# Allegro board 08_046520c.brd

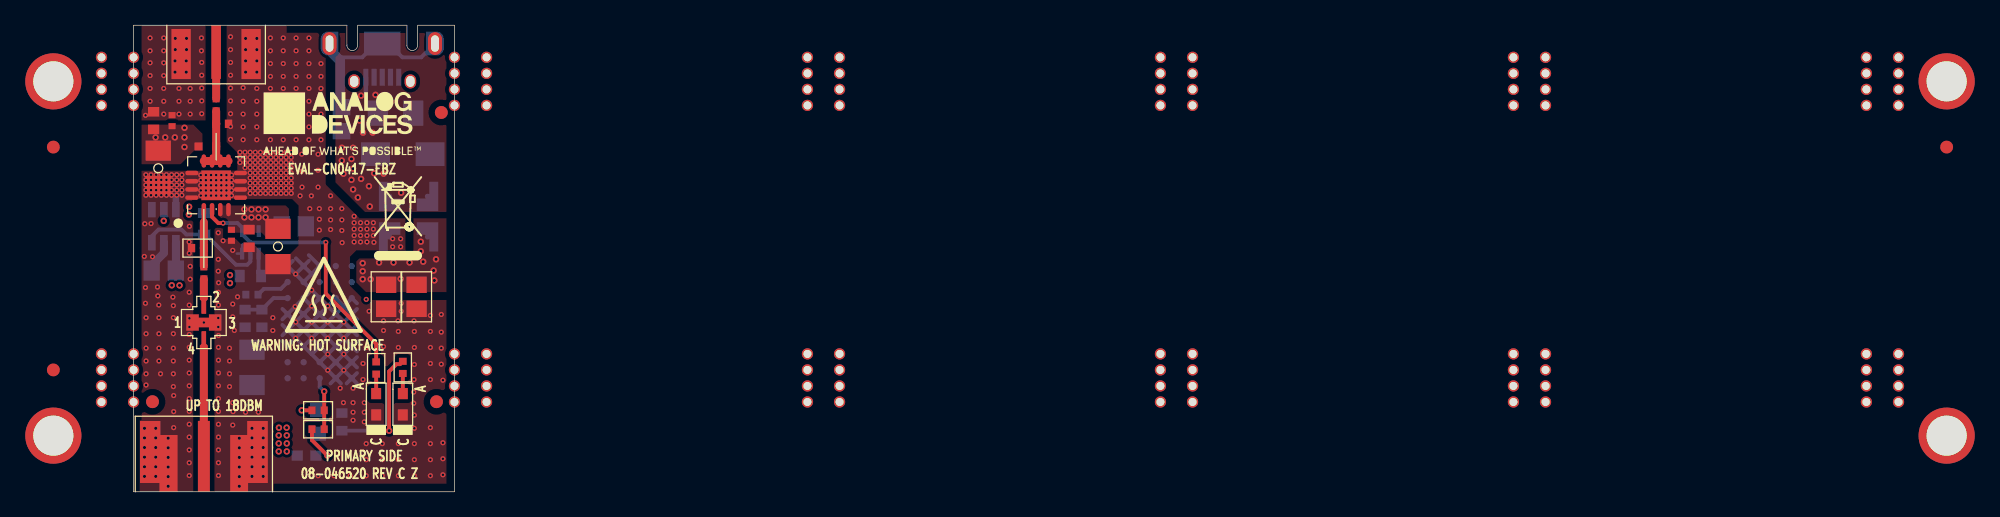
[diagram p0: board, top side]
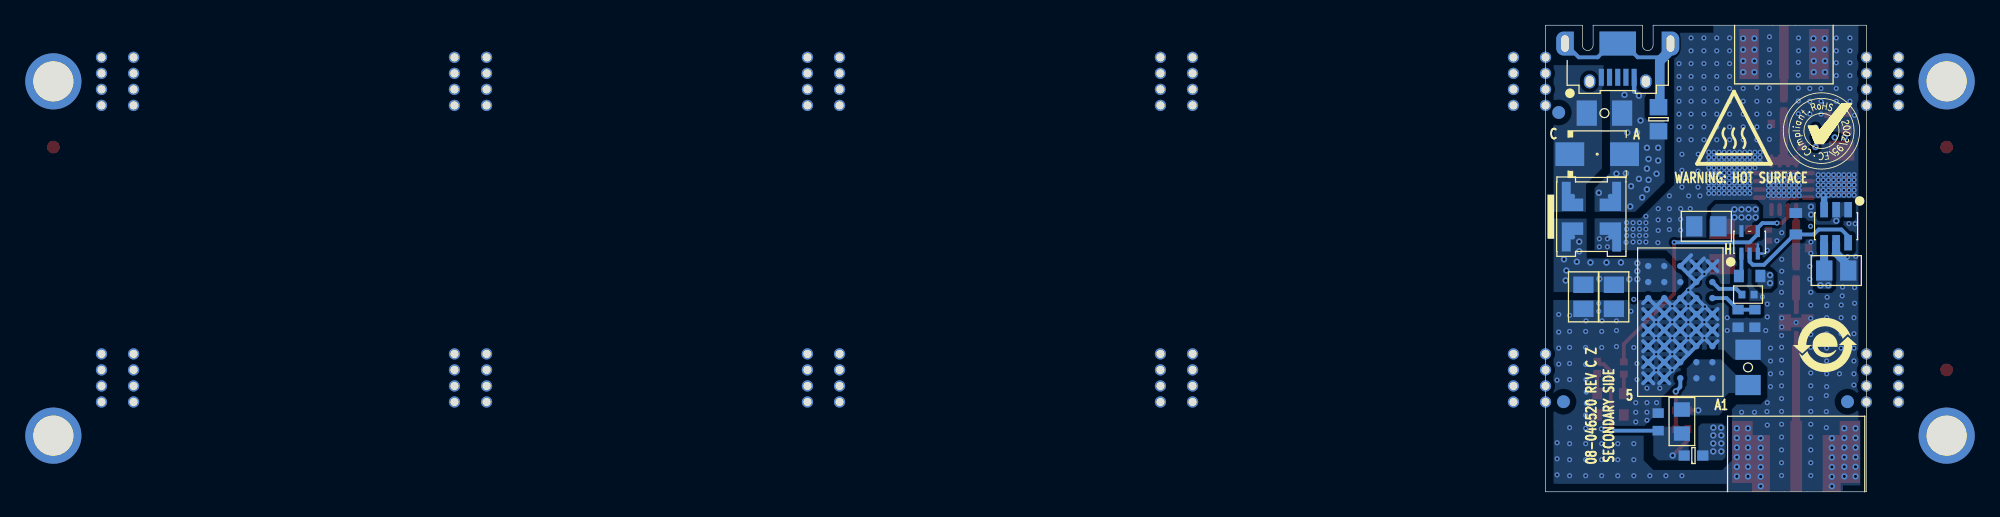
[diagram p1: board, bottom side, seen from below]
Outline 25.4 x 36.96 mm; copper layers: TOP, L2_GND, L3_GND, L4_PWR, L5_GND, BOTTOM. Coordinates in mm from the lower left corner of the outline.
Outline path: 0,36.96 16.88,36.96 16.88,35.38 arc(17.31,34.96) 17.74,35.38 17.74,36.96 21.63,36.96 21.63,35.38 arc(22.06,34.96) 22.49,35.38 22.49,36.96 25.4,36.96 25.4,0 0,0 0,36.96

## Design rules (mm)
constraint set DEFAULT: min track width 0.203
net group AMP: nets UNNAMED_7_ADL5606_I18_RFIN UNNAMED_7_ADL5606_I18_RFOUT1 UNNAMED_7_CAP_I75_N1 UNNAMED_7_CAP_I76_N2 UNNAMED_7_CNBNC5P_I149_CNTR UNNAMED_7_LINLTM8045_I104_FB

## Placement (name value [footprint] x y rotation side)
A1  ADL5606ACPZ  [QFN16_4X4_PAD2_36X2_36]  6.54 24.28 0 top
C1  20PF  [C0402#2]  5.56 17.34 90 top
C2  47UF  [C1206H71]  20.74 29.99 0 bottom
C3  4.7UF  [C0805H53]  22.4 15.44 90 bottom
C4  0.1UF  [C0805H53]  19.99 15.44 90 top
C5  0.1UF  [C0805H53]  22.4 15.44 90 top
C6  1UF  [C0603]  10.16 13.73 90 bottom
C7  0.1UF  [C0805H53]  19.99 15.44 90 bottom
C8  20PF  [C0402#2]  6.54 30.65 90 top
C9  1UF  [C0603]  8.83 13.73 90 bottom
C10  10UF  [C1206H71]  11.43 19.43 270 top
C11  0.01UF  [C0603]  9.14 20.07 270 top
C12  100pF  [C0402#2]  7.75 20.32 270 top
C13  10UF  [C1206H71]  1.96 25.63 270 top
C14  0.01UF  [C0603]  1.59 29.4 90 top
C15  100pF  [C0402#2]  3.05 29.4 90 top
C16  100uF  [C1206H71]  9.37 9.85 270 bottom
C17  1UF  [C0603]  16.48 5.53 270 bottom
C18  0.1UF  [C0805H53]  2.39 17.52 0 bottom
C19  0.1UF  [C0805H53]  12.67 21.03 180 bottom
CIN  2pF  [C0402]  5.07 19.3 0 top
COUT  3.3PF  [C0402]  7.03 29.15 180 top
D1  SMAJ5.0A-13-F  [DIOSMJ5_0]  21.31 26.74 180 bottom
DS1  LTST-C191KGKT  [LED0603_A]  21.31 6.93 90 top
DS2  SML-D12U1WT86  [LED0603_A]  19.2 6.93 90 top
E1  600OHM AT 100MEGHZ  [L0603]  13.69 2.87 180 bottom
FL1  2400-2500MEGHZ  [FL0805_A]  5.56 13.41 270 top
J1  132365-10  [CNSMARAL686W375H177]  5.56 0 270 top
J2  CON-SMA-EDGE-S  [CNSMARAL525W250H148]  6.53 36.96 90 top
L1  800OHMS AT 100MEGHZ  [L2020_A]  21.77 21.79 270 bottom
L2  18NH  [L7144A]  5.84 27.36 180 top
L3  1uH  [L0805]  14.61 5.56 270 bottom
NOREF  -  [unnamed]  109.22 31.88 0 top
NOREF#2  -  [unnamed]  -2.54 30.61 0 top
NOREF#3  -  [#2]  -6.35 4.44 0 top
NOREF#4  -  [unnamed]  0 8.38 0 top
NOREF#5  -  [unnamed]  83.82 33.15 0 top
NOREF#6  -  [unnamed]  25.4 30.61 0 top
NOREF#7  -  [unnamed]  109.22 10.92 0 top
NOREF#8  -  [unnamed]  23.98 7.13 0 top
NOREF#9  -  [unnamed]  137.16 10.92 0 top
NOREF#10  -  [#2]  25.4 0 0 top
NOREF#11  -  [#2]  27.94 0 0 top
NOREF#12  -  [unnamed]  27.94 33.15 0 top
NOREF#13  -  [unnamed]  27.94 9.65 0 top
NOREF#14  -  [unnamed]  0 30.61 0 top
NOREF#15  -  [unnamed]  81.28 9.65 0 top
NOREF#16  -  [#2]  -85.24 -81.42 0 top
NOREF#17  -  [#2]  18.41 36.96 180 top
NOREF#18  -  [unnamed]  24.36 30.05 0 top
NOREF#19  -  [unnamed]  139.7 30.61 0 top
NOREF#20  -  [unnamed]  -2.54 31.88 0 top
NOREF#21  -  [unnamed]  27.94 10.92 0 top
NOREF#22  -  [unnamed]  -2.54 34.42 0 top
NOREF#23  -  [unnamed]  111.76 9.65 0 top
NOREF#24  -  [unnamed]  83.82 31.88 0 top
NOREF#25  -  [unnamed]  139.7 10.92 0 top
NOREF#26  -  [unnamed]  83.82 34.42 0 top
NOREF#27  -  [#2]  83.82 0 0 top
NOREF#28  -  [unnamed]  137.16 33.15 0 top
NOREF#29  -  [#2]  200.49 202.45 0 top
NOREF#30  -  [unnamed]  -6.35 32.51 0 top
NOREF#31  -  [unnamed]  -2.54 7.11 0 top
NOREF#32  -  [unnamed]  53.34 31.88 0 top
NOREF#33  -  [unnamed]  0 33.15 0 top
NOREF#34  -  [#2]  200.49 216.62 0 top
NOREF#35  -  [unnamed]  -2.54 10.92 0 top
NOREF#36  -  [unnamed]  111.76 33.15 0 top
NOREF#37  -  [unnamed]  137.16 30.61 0 top
NOREF#38  -  [#2]  16.2 29.14 0 top
NOREF#39  -  [#2]  18.41 0 90 top
NOREF#40  -  [unnamed]  53.34 7.11 0 top
NOREF#41  -  [#2]  109.22 0 0 top
NOREF#42  -  [#2]  55.88 0 0 top
NOREF#43  -  [unnamed]  111.76 7.11 0 top
NOREF#44  -  [unnamed]  143.51 4.44 0 top
NOREF#45  -  [unnamed]  139.7 8.38 0 top
NOREF#46  -  [#2]  -2.54 0 0 top
NOREF#47  -  [unnamed]  25.4 33.15 0 top
NOREF#48  -  [#2]  -10.16 0 0 top
NOREF#49  -  [unnamed]  -6.35 4.44 0 top
NOREF#50  -  [unnamed]  55.88 10.92 0 top
NOREF#51  -  [unnamed]  111.76 34.42 0 top
NOREF#52  -  [unnamed]  53.34 9.65 0 top
NOREF#53  -  [unnamed]  81.28 8.38 0 top
NOREF#54  -  [unnamed]  109.22 8.38 0 top
NOREF#55  -  [unnamed]  139.7 31.88 0 top
NOREF#56  -  [#2]  20.73 18.39 0 top
NOREF#57  -  [unnamed]  1.5 7.13 0 top
NOREF#58  -  [unnamed]  25.4 9.65 0 top
NOREF#59  -  [unnamed]  109.22 9.65 0 top
NOREF#60  -  [unnamed]  53.34 33.15 0 top
NOREF#61  -  [#2]  -85.24 -81.42 0 top
NOREF#62  -  [unnamed]  55.88 30.61 0 top
NOREF#63  -  [unnamed]  137.16 9.65 0 top
NOREF#64  -  [unnamed]  25.4 8.38 0 top
NOREF#65  -  [unnamed]  81.28 34.42 0 top
NOREF#66  -  [unnamed]  143.51 32.51 0 top
NOREF#67  -  [unnamed]  111.76 31.88 0 top
NOREF#68  -  [#2]  -26.51 208.38 0 top
NOREF#69  -  [unnamed]  111.76 30.61 0 top
NOREF#70  -  [#2]  13.18 55.23 0 top
NOREF#71  -  [#2]  53.34 0 0 top
NOREF#72  -  [unnamed]  27.94 34.42 0 top
NOREF#73  -  [unnamed]  27.94 30.61 0 top
NOREF#74  -  [unnamed]  25.4 31.88 0 top
NOREF#75  -  [unnamed]  55.88 9.65 0 top
NOREF#76  -  [unnamed]  -2.54 8.38 0 top
NOREF#77  -  [unnamed]  53.34 10.92 0 top
NOREF#78  -  [#2]  198.13 184.67 90 top
NOREF#79  -  [#2]  0 0 0 top
NOREF#80  -  [unnamed]  53.34 34.42 0 top
NOREF#81  -  [unnamed]  81.28 33.15 0 top
NOREF#82  -  [unnamed]  55.88 33.15 0 top
NOREF#83  -  [unnamed]  109.22 30.61 0 top
NOREF#84  -  [unnamed]  53.34 30.61 0 top
NOREF#85  -  [unnamed]  109.22 34.42 0 top
NOREF#86  -  [#2]  51.59 145.53 0 top
NOREF#87  -  [#2]  206.54 214.31 90 top
NOREF#88  -  [unnamed]  81.28 30.61 0 top
NOREF#89  -  [unnamed]  0 31.88 0 top
NOREF#90  -  [unnamed]  139.7 7.11 0 top
NOREF#91  -  [unnamed]  139.7 34.42 0 top
NOREF#92  -  [unnamed]  27.94 7.11 0 top
NOREF#93  -  [unnamed]  111.76 8.38 0 top
NOREF#94  -  [unnamed]  25.4 10.92 0 top
NOREF#95  -  [unnamed]  0 9.65 0 top
NOREF#96  -  [unnamed]  139.7 33.15 0 top
NOREF#97  -  [unnamed]  -2.54 33.15 0 top
NOREF#98  -  [unnamed]  27.94 31.88 0 top
NOREF#99  -  [unnamed]  27.94 8.38 0 top
NOREF#100  -  [unnamed]  -6.35 27.3 0 top
NOREF#101  -  [#2]  -10.16 0 0 top
NOREF#102  -  [unnamed]  83.82 8.38 0 top
NOREF#103  -  [#2]  -10.16 36.96 0 top
NOREF#104  -  [#2]  194.67 114.19 0 top
NOREF#105  -  [unnamed]  25.4 34.42 0 top
NOREF#106  -  [unnamed]  55.88 31.88 0 top
NOREF#107  -  [#2]  139.7 0 0 top
NOREF#108  -  [#2]  32.54 141.72 0 top
NOREF#109  -  [unnamed]  83.82 7.11 0 top
NOREF#110  -  [unnamed]  0 34.42 0 top
NOREF#111  -  [unnamed]  137.16 8.38 0 top
NOREF#112  -  [unnamed]  109.22 33.15 0 top
NOREF#113  -  [unnamed]  83.82 10.92 0 top
NOREF#114  -  [#2]  189.47 214.34 0 top
NOREF#115  -  [unnamed]  111.76 10.92 0 top
NOREF#116  -  [unnamed]  83.82 30.61 0 top
NOREF#117  -  [#2]  81.28 0 0 top
NOREF#118  -  [#2]  1.22 27.55 0 top
NOREF#119  -  [unnamed]  81.28 7.11 0 top
NOREF#120  -  [#2]  147.32 0 0 top
NOREF#121  -  [unnamed]  -2.54 9.65 0 top
NOREF#122  -  [unnamed]  55.88 8.38 0 top
NOREF#123  -  [unnamed]  81.28 31.88 0 top
NOREF#124  -  [unnamed]  83.82 9.65 0 top
NOREF#125  -  [#2]  -69.38 316.18 0 top
NOREF#126  -  [#2]  -3.73 90.19 0 top
NOREF#127  -  [unnamed]  137.16 34.42 0 top
NOREF#128  -  [#2]  111.76 0 0 top
NOREF#129  -  [#2]  211.28 183.01 0 top
NOREF#130  -  [#2]  137.16 0 0 top
NOREF#131  -  [#2]  -85.24 -81.42 0 top
NOREF#132  -  [unnamed]  0 7.11 0 top
NOREF#133  -  [unnamed]  139.7 9.65 0 top
NOREF#134  -  [unnamed]  143.51 27.3 0 top
NOREF#135  -  [#2]  189.47 173.78 0 top
NOREF#136  -  [unnamed]  137.16 7.11 0 top
NOREF#137  -  [unnamed]  55.88 34.42 0 top
NOREF#138  -  [unnamed]  53.34 8.38 0 top
NOREF#139  -  [#2]  202.86 220.23 90 top
NOREF#140  -  [unnamed]  0 10.92 0 top
NOREF#141  -  [#2]  0 0 0 top
NOREF#142  -  [#2]  -6.35 4.44 0 top
NOREF#143  -  [unnamed]  137.16 31.88 0 top
NOREF#144  -  [#2]  0 36.96 270 top
NOREF#145  -  [unnamed]  55.88 7.11 0 top
NOREF#146  -  [unnamed]  81.28 10.92 0 top
NOREF#147  -  [unnamed]  -6.35 9.65 0 top
NOREF#148  -  [unnamed]  109.22 7.11 0 top
NOREF#149  -  [unnamed]  25.4 7.11 0 top
NOREF#150  -  [#2]  3.28 11.63 180 bottom
NOREF#151  -  [unnamed]  23.98 7.13 180 bottom
NOREF#152  -  [unnamed]  1.5 7.13 180 bottom
NOREF#153  -  [unnamed]  24.36 30.05 180 bottom
P1  47590-0001  [CNMOLEX47590-0001]  19.69 36.96 270 bottom
R1  1K  [R0805]  16.46 29.51 90 bottom
R2  60.4K  [R0402]  14.61 6.45 180 top
R3  182K  [R0402]  14.61 4.95 180 top
R4  301  [R0402]  21.31 9.85 90 top
R5  1K  [R0603]  5.59 21.23 90 bottom
R6  0  [R0603]  9.25 17.09 180 bottom
R7  365  [R0402]  19.2 9.8 90 top
RT  115K  [R0402]  9.37 15.62 180 bottom
U1  LTM8045MPY#PBF  [BGA40]  14.73 13.44 90 bottom
U2  ADT6402SRJZ  [TSOT23_6]  2.4 21.04 0 bottom
U3  74AHCT1G126SE-7  [SOT353]  9.25 19.76 180 bottom

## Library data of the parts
A1 = ADL5606: User Part Number: UPN; Tolerance: N/A; alternate symbols: (); part number: ADL5606_SM-ADL5606ACPZ,E026828,QFN16_4X4_PAD2_36X2_36; tolerance: N/A
C1 C8 = CAP: Tolerance: 5; User Part Number: UPN; alternate symbols: C0402L_ALT; part number: CAP_SM-20PF,50V,5,E033239,C0402; tolerance: 5
C2 = CAP: Tolerance: 20; User Part Number: UPN; alternate symbols: (); part number: CAP_SM-47UF,10V,20,E028092,C1206H71; tolerance: 20
C3 = CAP: Tolerance: 10; User Part Number: UPN; alternate symbols: (); part number: CAP_SM-4.7UF,25V,10,E025752,C0805H53; tolerance: 10
C4 C5 C7 C18 C19 = CAP: Tolerance: 10; User Part Number: UPN; alternate symbols: (); part number: CAP_SM-0.1UF,50V,10,E033336,C0805H53; tolerance: 10
C6 C9 C17 = CAP: Tolerance: 10; User Part Number: UPN; alternate symbols: C0603L_ALT; part number: CAP_SM-1UF,25V,10,E025743,C0603; tolerance: 10
C10 C13 = CAP: Tolerance: 10; User Part Number: UPN; alternate symbols: (); part number: CAP_SM-10UF,10V,10,E027443,C1206H71; tolerance: 10
C11 C14 = CAP: Tolerance: 10; User Part Number: UPN; alternate symbols: C0603L_ALT; part number: CAP_SM-0.01UF,100V,10,E032297,C0603; tolerance: 10
C12 C15 = CAP: Tolerance: 5; User Part Number: UPN; alternate symbols: C0402L_ALT; part number: CAP_SM-100PF,50V,5,E022402,C0402; tolerance: 5
C16 = CAP: Tolerance: 20; User Part Number: UPN; alternate symbols: (); part number: CAP_SM-100UF,6.3V,20,E016591,C1206H71; tolerance: 20
CIN = CAP: Tolerance: 0.25pF; User Part Number: UPN; alternate symbols: C0402L_ALT; part number: CAP_SM-2PF,50V,0.25PF,E012548,C0402; tolerance: 0.25pF
COUT = CAP: Tolerance: 0.1PF; User Part Number: UPN; alternate symbols: C0402L_ALT; part number: CAP_SM-3.3PF,50V,0.1PF,E027135,C0402; tolerance: 0.1PF
D1 = DIO: Tolerance: N/A; User Part Number: UPN; alternate symbols: (); part number: DIO_SM-SMAJ5.0A-13-F,5V,N/A,E001108,DIOSMJ5_0; tolerance: N/A
DS1 = DIOLED: User Part Number: UPN; Tolerance: N/A; alternate symbols: (); part number: DIOLED_SM-LTST-C191KGKT,2V,N/A,E033001,LED0603_A; tolerance: N/A
DS2 = DIOLED: User Part Number: UPN; Tolerance: N/A; alternate symbols: (); part number: DIOLED_SM-SML-D12U1WT86,2.2V,N/A,E037111,LED0603_A; tolerance: N/A
E1 = FERRITE: Tolerance: 25; User Part Number: UPN; alternate symbols: (); part number: FERRITE_SM-600OHM AT 100MEGHZ,25,E028908,L0603; tolerance: 25
FL1 = FLTRBP4P_V2: User Part Number: UPN; Tolerance: N/A; alternate symbols: (); part number: FLTRBP4P_V2_SM-2400-2500MEGHZ,E023131,FL0805_A; tolerance: N/A
J1 = CNBNC5P: alternate symbols: (CNSMARAL686W375H177_CNSMARAL535W256H152); part number: CNBNC5P_SM-132365-10,E033180,CNSMARAL686W375H177; tolerance: N/A
J2 = CNBNC5P: Tolerance: N/A; User Part Number: UPN; alternate symbols: (); part number: CNBNC5P_SM-CON-SMA-EDGE-S,E028678,CNSMARAL525W250H148; tolerance: N/A
L1 = CHOKE4P: User Part Number: UPN; Tolerance: N/A; alternate symbols: (); part number: CHOKE4P_SM-800OHMS AT 100MEGHZ,N/A,E027130,L2020_A; tolerance: N/A
L2 = IND: Tolerance: 5; User Part Number: UPN; alternate symbols: (); part number: IND_SM-18NH,5,E029275,L7144A; tolerance: 5
L3 = IND: Tolerance: 20; User Part Number: UPN; alternate symbols: (L0805L); part number: IND_SM-1UH,20,E010399,L0805; tolerance: 20
P1 = CN5P_3SHLD: User Part Number: UPN; Tolerance: N/A; alternate symbols: (); part number: CN5P_3SHLD_SM-47590-0001,E015753,CNMOLEX47590-0001; tolerance: N/A
R1 = RES: Tolerance: 1; User Part Number: UPN; alternate symbols: (R0805L); part number: RES_SM-1K,E023448,1/3W,1,R0805; tolerance: 1
R2 = RES: Tolerance: 1; User Part Number: UPN; alternate symbols: (R0402L); part number: RES_SM-60.4K,E022436,1/10W,1,R0402; tolerance: 1
R3 = RES: Tolerance: 1; User Part Number: UPN; alternate symbols: (R0402L); part number: RES_SM-182K,E025180,1/10W,1,R0402; tolerance: 1
R4 = RES: Tolerance: 1; User Part Number: UPN; alternate symbols: (R0402L); part number: RES_SM-301,E011195,1/16W,1,R0402; tolerance: 1
R5 = RES: User Part Number: UPN; Tolerance: 1; alternate symbols: (R0603L); part number: RES_SM-1K,E003678,1/10W,1,R0603; tolerance: 1
R6 = RES: User Part Number: UPN; Tolerance: 5; alternate symbols: (R0603L); part number: RES_SM-0,E006826,1/10W,5,R0603; tolerance: 5
R7 = RES: Tolerance: 1; User Part Number: UPN; alternate symbols: (R0402L); part number: RES_SM-365,E028356,1/10W,1,R0402; tolerance: 1
RT = RES: Tolerance: 1; User Part Number: UPN; alternate symbols: (R0402L); part number: RES_SM-115K,E025179,1/10W,1,R0402; tolerance: 1
U1 = LINLTM8045: Tolerance: N/A; User Part Number: UPN; alternate symbols: (); part number: LINLTM8045_SM-LTM8045MPY#PBF,E028897,BGA40; tolerance: N/A
U2 = ADT6402: User Part Number: UPN; Tolerance: N/A; alternate symbols: (); part number: ADT6402_SM-ADT6402SRJZ,E035980,TSOT23_6; tolerance: N/A
U3 = 741G126: User Part Number: UPN; Tolerance: N/A; alternate symbols: (); part number: 741G126_SM-74AHCT1G126SE-7,E0371122,SOT353; tolerance: N/A

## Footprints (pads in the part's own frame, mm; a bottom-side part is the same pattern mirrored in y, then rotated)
BGA40
  round 0.508 smd: A1(-4.445,-2.54) A2(-4.445,-1.27) A3(-4.445,0) A4(-4.445,1.27) A5(-4.445,2.54) B1(-3.175,-2.54) B2(-3.175,-1.27) B3(-3.175,0) B4(-3.175,1.27) B5(-3.175,2.54) C1(-1.905,-2.54) C2(-1.905,-1.27) C3(-1.905,0) C4(-1.905,1.27) C5(-1.905,2.54) D1(-0.635,-2.54) D2(-0.635,-1.27) D3(-0.635,0) D4(-0.635,1.27) D5(-0.635,2.54) E1(0.635,-2.54) E2(0.635,-1.27) E3(0.635,0) E4(0.635,1.27) E5(0.635,2.54) F1(1.905,-2.54) F2(1.905,-1.27) F3(1.905,0) F4(1.905,1.27) F5(1.905,2.54) G1(3.175,-2.54) G2(3.175,-1.27) G3(3.175,0) G4(3.175,1.27) G5(3.175,2.54) H1(4.445,-2.54) H2(4.445,-1.27) H3(4.445,0) H4(4.445,1.27) H5(4.445,2.54)
C0402
  rect 0.584x0.66 smd: 1(-0.49,0) 2(0.49,0)
C0402#2
  rect 0.483x0.559 smd: 1(-0.438,0) 2(0.438,0)
C0603
  rect 0.762x0.889 smd: 1(-0.699,0) 2(0.699,0)
C0805H53
  rect 1.295x1.6 smd: 1(-0.953,0) 2(0.953,0)
C1206H71
  rect 1.6x2.007 smd: 1(-1.397,0) 2(1.397,0)
CNMOLEX47590-0001
  oval 1.118x0.914 hole 0.864x0.66: (4.45,-2.225) (4.45,2.225)
  rect 1.346x0.406 smd: 1(4.123,-1.3) 2(4.123,-0.65) 3(4.123,0) 4(4.123,0.65) 5(4.123,1.3)
  oval 1.803x1.118 hole 1.295x0.61: SH1(1.45,4.175) SH3(1.45,-4.175)
  rect 1.905x2.896 smd: SH2(1.45,0)
CNSMARAL525W250H148
  rect 4.242x0.762 smd: 1(-2.121,0)
  rect 3.962x1.499 smd: 2(-2.281,2.77) 3(-2.281,2.77) 4(-2.281,-2.77) 5(-2.281,-2.77)
CNSMARAL686W375H177
  rect 5.613x0.94 smd: 1(-2.807,0)
  custom 0.737x0.737 smd: 2(-2.801,3.576) 3(-2.801,-3.576) 4(-2.801,3.576) 5(-2.801,-3.576)
DIOSMJ5_0
  rect 2.286x1.88 smd: A(2.164,0) C(-2.164,0)
FL0805_A
  rect 1.295x0.986 smd: 1(0,-0.895) 3(0,0.895)
  rect 0.991x0.356 smd: 2(-1.195,0) 4(1.195,0)
L0603
  rect 0.889x0.813 smd: 1(-0.737,0) 2(0.737,0)
L0805
  rect 1.143x1.27 smd: 1(-0.953,0) 2(0.953,0)
L2020_A
  custom 0.425x0.425 smd: 1(-1.606,-1.501) 2(1.606,-1.501) 3(1.606,1.501) 4(-1.606,1.501)
L7144A
  rect 0.635x0.635 smd: 1(-0.699,0) 2(0.699,0)
LED0603_A
  rect 0.889x0.787 smd: A(0.845,0) C(-0.845,0)
QFN16_4X4_PAD2_36X2_36
  oval 0.356x1.041 smd: 1(-0.975,-1.925) 2(-0.325,-1.925) 3(0.325,-1.925) 4(0.975,-1.925) 9(0.975,1.925) 10(0.325,1.925) 11(-0.325,1.925) 12(-0.975,1.925)
  oval 1.041x0.356 smd: 5(1.925,-0.975) 6(1.925,-0.325) 7(1.925,0.325) 8(1.925,0.975) 13(-1.925,0.975) 14(-1.925,0.325) 15(-1.925,-0.325) 16(-1.925,-0.975)
  rect 2.352x2.352 smd: PAD(0,0)
R0402
  rect 0.559x0.61 smd: 1(-0.483,0) 2(0.483,0)
R0603
  rect 0.787x0.991 smd: 1(-0.85,0) 2(0.85,0)
R0805
  rect 1.295x1.397 smd: 1(-0.953,0) 2(0.953,0)
SOT353
  rect 0.33x0.94 smd: 1(-0.65,-0.89) 2(0,-0.89) 3(0.65,-0.89) 4(0.65,0.89) 5(-0.65,0.89)
TSOT23_6
  rect 0.61x1.219 smd: 1(-0.95,-1.31) 2(0,-1.31) 3(0.95,-1.31) 4(0.95,1.31) 5(0,1.31) 6(-0.95,1.31)
unnamed
  round 0.889 hole 0.635 unplated: (0,0)

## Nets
5V_VCC: A1.3(VCC) A1.4 C10.1 C11.1 C12.1 C13.1 C14.1 C15.1 C18.2(N2) C19.2(N2) E1.2(N2) L2.2(N2) R5.2(N2) R6.2(N2) U2.1 U2.2 U2.4(VCC) U3.5
GND: A1.5 A1.6 A1.7 A1.8 A1.13 A1.14 A1.15 A1.16 A1.PAD C3.1 C4.1 C5.1 C6.1 C7.1 C9.1 C10.2(N2) C11.2(N2) C12.2(N2) C13.2(N2) C14.2(N2) C15.2(N2) C16.1 C17.1 C18.1 C19.1 CIN.1 COUT.1 DS1.C DS2.C FL1.1 FL1.3 J1.2 J1.3 J1.4 J1.5(SH4) J2.2 J2.3 J2.4 J2.5(SH4) L1.3 RT.2(N2) U1.A4 U1.A5 U1.B3 U1.B4 U1.B5(VOUT-_4) U1.C1 U1.C2 U1.C3 U1.C4 U1.C5 U1.D1 U1.D2 U1.D3 U1.D4 U1.D5 U1.E1 U1.E2 U1.E3 U1.E4 U1.E5 U1.F2 U1.F3 U1.F4 U1.F5 U1.G2 U1.H1 U1.H2 U1.H3 U2.3 U2.5 U3.3
PGND: C2.1 D1.A(P) L1.4(N4) P1.5 R1.1
DISABLE: A1.2 R7.2(N2) U3.4(Y)
UNNAMED_7_741G126_I166_A: R5.1 U2.6 U3.2
UNNAMED_7_741G126_I166_OE: R6.1 U3.1
UNNAMED_7_ADL5606_I18_RFIN: A1.1 C1.2(N2) CIN.2(N2)
UNNAMED_7_ADL5606_I18_RFOUT1: A1.9 A1.10 A1.11 A1.12 C8.1 COUT.2(N2) L2.1
UNNAMED_7_CAP_I75_N1: C1.1 FL1.2(OUT)
UNNAMED_7_CAP_I76_N2: C8.2(N2) J2.1
UNNAMED_7_CAP_I108_N2: C16.2(N2) L3.1 R2.2(N2) U1.A1 U1.A2 U1.B1 U1.B2
UNNAMED_7_CAP_I113_N2: C3.2(N2) C4.2(N2) C5.2(N2) C7.2(N2) L1.2 U1.G3 U1.G4 U1.G5 U1.H4 U1.H5
UNNAMED_7_CAP_I120_N2: C2.2(N2) D1.C L1.1 P1.1
UNNAMED_7_CAP_I132_N2: C6.2(N2) C9.2(N2) U1.F1
UNNAMED_7_CN5P3SHLD_I127_N6: P1.SH1 P1.SH2 P1.SH3(N8) R1.2(N2)
UNNAMED_7_CNBNC5P_I149_CNTR: FL1.4 J1.1
UNNAMED_7_DIOLED_I150_P: DS1.A(P) R4.1
UNNAMED_7_DIOLED_I172_P: DS2.A(P) R7.1
UNNAMED_7_FERRITE_I107_N1: C17.2(N2) E1.1 L3.2(N2) R3.2(N2) R4.2(N2)
UNNAMED_7_LINLTM8045_I104_FB: R2.1 R3.1 U1.A3
UNNAMED_7_LINLTM8045_I104_RT: RT.1 U1.G1

Pads without a net: P1 2 3 4

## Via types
v1: diameter 0.406, hole 0.203, TOP to BOTTOM, 466 vias
v2: diameter 0.508, hole 0.254, TOP to BOTTOM, 119 vias

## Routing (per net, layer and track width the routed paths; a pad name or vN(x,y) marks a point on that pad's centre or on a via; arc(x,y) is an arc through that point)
5V_VCC: length 2.2
  BOTTOM w0.635: C18.2 3.35,17.53 U2.4
  vias: v2(1.74,28.07) v2(2.39,21.46) v2(2.51,28.07) v2(3.02,16.36) v2(3.27,28.07) v2(3.64,16.35) v2(4.03,28.83) v2(4.03,28.07) v2(4.03,27.31) v2(4.39,22.58) v2(4.38,21.96) v2(7.63,17.16) v2(7.63,16.53) v2(8.77,22.37) v2(8.77,21.74) v2(9.33,22.37) v2(9.33,21.74) v2(9.89,22.37) v2(9.89,21.74) v2(10.45,22.37) v2(10.45,21.74) v2(11.51,5.08) v2(11.49,4.46) v2(11.49,3.83) v2(11.49,3.19) v2(12.12,5.08) v2(12.13,4.46) v2(12.13,3.83) v2(12.13,3.19)
GND: length 86.8
  BOTTOM w0.203: 8.6,19.59 U3.3 8.18,18.87
  BOTTOM w0.305: U1.C4 v1(16.64,12.17) ; U1.C4 v1(15.37,10.9) ; U1.C4 v1(15.37,12.17) ; U1.C4 v1(16.64,10.9) ; v1(16.64,12.17) U1.D5 ; v1(16.64,12.17) U1.C5 ; v1(16.64,12.17) U1.D4 ; v1(14.1,15.98) U1.F2 ; v1(14.1,15.98) U1.F3 ; v1(14.1,15.98) U1.G2 ; U1.F2 v1(12.79,14.67) ; U1.F2 v1(14.1,14.71) ; 16.64,14.71 U1.E4 ; 16.64,14.71 U1.E5 ; 16.64,14.71 U1.F5 17.68,14.93 ; 16.64,14.71 U1.F4 v1(15.37,14.71) ; U1.E4 v1(15.37,14.71) ; U1.E4 v1(15.37,13.44) ; U1.E4 v1(16.64,13.44) ; 16.86,8.58 U1.A5 ; U1.A5 v1(16.64,9.63) ; U1.A5 17.68,9.4 ; U1.A5 17.68,8.58 ; v1(12.83,12.17) U1.D2 ; v1(12.83,12.17) U1.C2 ; v1(12.83,12.17) U1.C1 11.78,11.94 ; v1(12.83,12.17) U1.D1 ; U1.D2 v1(14.1,13.44) ; U1.D2 v1(12.83,13.44) ; U1.D2 v1(14.1,12.17) ; U1.F3 v1(14.1,14.71) ; U1.F3 v1(15.37,14.71) ; 14.1,10.9 U1.C3 ; 14.1,10.9 U1.C2 ; 14.1,10.9 U1.B3 ; U1.C3 v1(15.37,10.9) ; U1.C3 v1(15.37,12.17) ; U1.C3 v1(14.1,12.17) ; v1(12.79,14.67) U1.E1 ; v1(12.79,14.67) 13.39,14.07 U1.E2 ; U1.E1 v1(12.83,13.44) ; U1.E1 11.78,13.66 ; U1.E1 11.78,14.48 ; U1.B3 v1(15.37,9.63) ; U1.B3 v1(15.37,10.9) ; v1(15.37,9.63) U1.B4 ; v1(15.37,9.63) U1.A4 ; 13.87,18.74 U1.H3 14.1,17.25 ; U1.C5 17.68,11.12 ; U1.C5 v1(16.64,10.9) ; U1.C5 17.68,11.94 ; v1(15.37,14.71) U1.E3 ; v1(14.1,13.44) U1.D3 ; v1(14.1,13.44) U1.E2 ; v1(14.1,13.44) U1.E3 ; U1.D3 v1(15.37,12.17) ; U1.D3 v1(15.37,13.44) ; U1.D3 v1(14.1,12.17) ; U1.E2 v1(14.1,14.71) ; U1.E2 v1(12.83,13.44) ; v1(14.1,14.71) U1.E3 ; v1(15.37,10.9) U1.B4 ; U1.B4 v1(16.64,10.9) ; U1.B4 v1(16.64,9.63) ; U1.C2 v1(14.1,12.17) ; v1(12.83,13.44) U1.D1 ; U1.H2 v1(12.83,17.25) ; U1.H2 12.85,18.49 ; U1.H2 13.87,18.29 ; U1.H2 14.1,17.25 ; v1(12.83,17.25) U1.G2 ; v1(12.83,17.25) U1.H1 ; U1.G2 14.1,17.25 ; U1.D5 17.68,13.21 ; U1.D5 17.68,12.39 ; U1.D5 v1(16.64,13.44) ; v1(16.64,10.9) U1.B5 ; U1.D1 11.78,12.39 ; U1.D1 11.78,13.21 ; 15.59,8.58 U1.A4 ; U1.A4 16.41,8.58 ; U1.A4 v1(16.64,9.63) ; v1(16.64,9.63) U1.B5 ; U1.D4 v1(15.37,12.17) ; U1.D4 v1(15.37,13.44) ; U1.D4 v1(16.64,13.44) ; U1.E5 v1(16.64,13.44) ; U1.E5 17.68,13.66 ; U1.E5 17.68,14.48 ; U1.B5 17.68,10.67 ; U1.B5 17.68,9.85 ; U1.H1 11.78,17.47 ; U1.H1 12.6,18.29 ; U1.H1 11.78,18.29 ; U1.E3 v1(15.37,13.44)
  BOTTOM w0.508: v1(3.41,23.49) 3.35,23.43 U2.3
  BOTTOM w0.635: U2.5 2.4,18.91 1.43,17.94 C18.1
  vias: v1(0.89,21.23) v1(0.85,18.64) v1(0.95,29.82) v1(0.97,25.11) v1(0.97,24.71) v1(0.97,24.3) v1(0.97,23.9) v1(0.97,23.49) v1(0.94,16.18) v1(0.94,14.93) v1(0.99,13.79) v1(0.99,12.52) v1(0.99,11.38) v1(0.99,10.36) v1(0.99,9.34) v1(0.99,8.46) v1(1.31,35.95) v1(1.31,34.94) v1(1.31,33.98) v1(1.31,32.97) v1(1.31,31.95) v1(1.31,30.93) v1(1.38,25.11) v1(1.38,24.71) v1(1.38,24.3) v1(1.38,23.9) v1(1.38,23.49) v1(1.38,21.24) v1(1.5,18.62) v1(1.79,25.11) v1(1.79,24.71) v1(1.79,24.3) v1(1.79,23.9) v1(1.79,23.49) v1(1.89,16.22) v1(1.92,15.52) v1(1.99,14.79) v1(2.01,13.79) v1(2.01,12.52) v1(2.01,11.38) v1(2.01,10.36) v1(2.19,25.11) v1(2.19,24.71) v1(2.19,24.3) v1(2.19,23.9) v1(2.19,23.49) v1(2.13,9.34) v1(2.39,35.95) v1(2.39,34.94) v1(2.39,33.98) v1(2.39,32.97) v1(2.39,31.95) v1(2.39,30.93) v1(2.39,29.92) v1(2.6,25.11) v1(2.6,24.71) v1(2.6,24.3) v1(2.6,23.9) v1(2.6,23.49) v1(3.01,25.11) v1(3.01,24.71) v1(3.01,24.3) v1(3.01,23.9) v1(3.01,23.49) v1(3.11,15.42) v1(3.15,14.74) v1(3.15,13.79) v1(3.15,12.52) v1(3.15,11.38) v1(3.15,10.36) v1(3.15,9.34) v1(3.15,8.33) v1(3.17,7.62) v1(3.17,6.35) v1(3.17,5.08) v1(3.41,25.11) v1(3.41,24.71) v1(3.41,24.3) v1(3.41,23.9) v1(3.59,31.95) v1(3.59,30.93) v1(3.59,29.92) v1(3.82,25.11) v1(3.82,24.71) v1(3.82,24.3) v1(3.82,23.9) v1(3.82,23.49) v1(4.39,19.78) v1(4.41,18.89) v1(4.41,15.8) v1(4.41,14.79) v1(4.41,12.46) v1(4.41,11.44) v1(4.41,10.43) v1(4.41,9.41) v1(4.41,8.39) v1(4.41,7.38) v1(4.41,6.36) v1(4.41,5.35) v1(4.41,4.33) v1(4.41,3.31) v1(4.41,2.3) v1(4.41,1.28) v1(4.48,31.95) v1(4.48,30.93) v1(4.48,29.92) v1(4.42,21.03) v1(4.48,17.85) v1(4.48,16.84) v1(4.42,13.74) v1(4.42,13.05) v1(5.37,35.95) v1(5.37,34.94) v1(5.39,34.01) v1(5.39,33) v1(5.39,31.98) v1(5.39,30.96) v1(5.39,29.95) v1(5.32,25.09) v1(5.32,24.68) v1(5.32,24.28) v1(5.32,23.87) v1(5.32,23.46) v1(5.56,13.41) v1(5.72,25.09) v1(5.72,24.68) v1(5.72,24.28) v1(5.72,23.87) v1(5.72,23.46) v1(6.13,25.09) v1(6.13,24.68) v1(6.13,24.28) v1(6.13,23.87) v1(6.13,23.46) v1(6.54,25.09) v1(6.54,24.68) v1(6.54,24.28) v1(6.54,23.87) v1(6.54,23.46) v1(6.71,20.52) v1(6.71,18.41) v1(6.71,17.47) v1(6.71,13.76) v1(6.71,13.05) v1(6.73,16.56) v1(6.72,15.8) v1(6.72,14.79) v1(6.72,12.37) v1(6.72,11.44) v1(6.72,10.43) v1(6.72,9.41) v1(6.72,8.39) v1(6.72,7.38) v1(6.72,6.36) v1(6.72,5.35) v1(6.72,4.33) v1(6.72,3.31) v1(6.72,2.3) v1(6.72,1.28) v1(6.94,25.09) v1(6.94,24.68) v1(6.94,24.28) v1(6.94,23.87) v1(6.94,23.46) v1(7.09,19.89) v1(7.35,25.09) v1(7.35,24.68) v1(7.35,24.28) v1(7.35,23.87) v1(7.35,23.46) v1(7.59,11.38) v1(7.59,10.36) v1(7.59,9.34) v1(7.59,8.33) v1(7.68,36.04) v1(7.68,35.03) v1(7.68,34.01) v1(7.68,33) v1(7.68,31.98) v1(7.68,30.96) v1(7.68,29.95) v1(7.68,28.93) v1(7.68,27.92) v1(7.76,25.09) v1(7.76,24.68) v1(7.76,24.28) v1(7.76,23.87) v1(7.76,23.46) v1(7.85,19.12) v1(7.85,14.87) v1(7.85,13.85) v1(7.85,7.06) v1(7.87,6.35) v1(7.85,5.28) v1(7.98,12.77) v1(8.23,15.44) v1(8.42,26.89) v1(8.42,26.49) v1(8.42,26.08) v1(8.67,32.01) v1(8.67,30.93) v1(8.67,29.92) v1(8.67,28.9) v1(8.67,27.89) v1(8.82,26.89) v1(8.82,26.49) v1(8.82,26.08) v1(8.82,25.67) v1(8.86,6.3) v1(9.23,26.89) v1(9.23,26.49) v1(9.23,26.08) v1(9.23,25.67) v1(9.23,25.27) v1(9.23,24.86) v1(9.23,24.45) v1(9.23,24.05) v1(9.23,23.64) v1(9.64,26.89) v1(9.64,26.49) v1(9.64,26.08) v1(9.64,25.67) v1(9.64,25.27) v1(9.64,24.86) v1(9.64,24.45) v1(9.64,24.05) v1(9.64,23.64) v1(9.75,31.95) v1(9.75,30.93) v1(9.75,29.92) v1(9.75,28.9) v1(9.75,27.89) v1(9.88,6.3) v1(10.04,26.89) v1(10.04,26.49) v1(10.04,26.08) v1(10.04,25.67) v1(10.04,25.27) v1(10.04,24.86) v1(10.04,24.45) v1(10.04,24.05) v1(10.04,23.64) v1(10.45,26.89) v1(10.45,26.49) v1(10.45,26.08) v1(10.45,25.67) v1(10.45,25.27) v1(10.45,24.86) v1(10.45,24.45) v1(10.45,24.05) v1(10.45,23.64) v1(10.83,35.95) v1(10.83,34.94) v1(10.83,33.92) v1(10.83,32.9) v1(10.83,31.95) v1(10.83,30.93) v1(10.83,29.92) v1(10.83,28.9) v1(10.83,27.89) v1(10.86,26.89) v1(10.86,26.49) v1(10.86,26.08) v1(10.86,25.67) v1(10.86,25.27) v1(10.86,24.86) v1(10.86,24.45) v1(10.86,24.05) v1(10.86,23.64) v1(11.02,13.79) v1(11.02,12.77) v1(11.26,26.89) v1(11.26,26.49) v1(11.26,26.08) v1(11.26,25.67) v1(11.26,25.27) v1(11.26,24.86) v1(11.26,24.45) v1(11.26,24.05) v1(11.26,23.64) v1(11.67,26.89) v1(11.67,26.49) v1(11.67,26.08) v1(11.67,25.67) v1(11.67,25.27) v1(11.67,24.86) v1(11.67,24.45) v1(11.67,24.05) v1(11.67,23.64) v1(11.85,35.95) v1(11.85,34.94) v1(11.85,33.92) v1(11.85,32.9) v1(11.85,31.95) v1(11.85,30.93) v1(11.85,29.92) v1(11.85,28.9) v1(11.85,27.89) v1(12.07,26.89) v1(12.07,26.49) v1(12.07,26.08) v1(12.07,25.67) v1(12.07,25.27) v1(12.07,24.86) v1(12.07,24.45) v1(12.07,24.05) v1(12.07,23.64) v1(12.48,26.9) v1(12.48,26.49) v1(12.48,26.08) v1(12.48,25.67) v1(12.48,25.27) v1(12.48,24.86) v1(12.48,24.45) v1(12.48,24.05) v1(12.48,23.64) v1(12.86,35.95) v1(12.86,34.94) v1(12.86,33.92) v1(12.86,32.9) v1(12.86,31.95) v1(12.86,30.93) v1(12.86,29.92) v1(12.86,28.9) v1(12.86,27.89) v1(13.18,23.44) v1(13.31,26.74) v1(13.34,25.4) v1(13.34,24.13) v1(13.88,35.95) v1(13.88,34.94) v1(13.88,33.92) v1(13.88,32.9) v1(13.88,31.95) v1(13.88,30.93) v1(13.88,29.92) v1(13.88,28.9) v1(13.88,27.89) v1(13.94,22.43) v1(14.07,23.44) v1(14.61,26.73) v1(14.61,25.46) v1(14.61,24.13) v1(14.61,1.27) v1(14.71,22.43) v1(14.71,21.59) v1(14.71,20.72) v1(14.83,33.92) v1(14.83,32.9) v1(14.83,31.95) v1(14.83,30.93) v1(14.83,29.92) v1(14.83,28.9) v1(14.83,27.89) v1(15.6,23.44) v1(15.6,22.43) v1(15.6,21.54) v1(15.6,20.77) v1(15.88,1.27) v1(16.36,8.2) v1(16.48,22.43) v1(16.48,21.54) v1(16.48,20.7) v1(16.51,19.73) v1(16.61,7.06) v1(17.14,1.27) v1(17.37,8.2) v1(17.37,7.06) v1(17.37,6.3) v1(17.37,5.66) v1(17.46,21.82) v1(17.46,21.31) v1(17.46,20.8) v1(17.46,20.3) v1(17.46,19.79) v1(17.96,21.31) v1(17.96,20.8) v1(17.96,20.3) v1(17.96,19.79) v1(18.16,10.16) v1(18.16,8.89) v1(18.26,7.06) v1(18.26,6.3) v1(18.26,5.53) v1(18.47,21.31) v1(18.47,20.8) v1(18.47,20.3) v1(18.47,19.79) v1(18.41,15.24) v1(18.41,11.43) v1(18.41,3.81) v1(18.41,2.54) v1(18.41,1.27) v1(18.64,14.3) v1(18.98,21.31) v1(18.98,20.8) v1(18.98,20.3) v1(19.02,19.76) v1(19.69,3.81) v1(19.69,2.54) v1(19.69,1.27) v1(19.79,13.54) v1(19.79,12.77) v1(19.79,11.5) v1(20.5,20.04) v1(20.5,19.41) v1(20.93,13.54) v1(20.95,12.7) v1(20.95,11.43) v1(20.98,4.98) v1(20.95,3.81) v1(20.95,2.54) v1(20.95,1.27) v1(21.14,20.04) v1(21.14,19.41) v1(21.18,14.93) v1(21.18,14.3) v1(22.2,13.54) v1(22.2,8.89) v1(22.17,7.9) v1(22.17,7.01) v1(22.23,12.7) v1(22.23,11.43) v1(22.22,10.08) v1(22.22,6.07) v1(22.22,5.03) v1(22.23,3.81) v1(22.23,2.54) v1(22.23,1.27) v1(23.49,13.97) v1(23.49,12.7) v1(23.49,11.43) v1(23.49,10.16) v1(23.49,8.89) v1(23.49,5.08) v1(23.49,3.81) v1(23.49,2.54) v1(23.49,1.27) v1(24.36,14.04) v1(24.36,12.65) v1(24.36,11.38) v1(24.36,10.11) v1(24.49,8.84) v1(24.49,3.88) v1(24.49,2.61) v1(24.49,1.34) v2(0.86,5.03) v2(0.86,4.26) v2(0.86,3.5) v2(0.86,2.74) v2(0.86,1.98) v2(0.86,1.22) v2(1.75,5.03) v2(1.75,4.26) v2(1.75,3.5) v2(1.75,2.74) v2(1.75,1.98) v2(1.75,1.22) v2(2.74,4.24) v2(2.74,3.48) v2(2.74,2.72) v2(2.74,1.96) v2(2.74,1.2) v2(2.74,0.43) v2(3.3,35.92) v2(3.3,35.03) v2(3.28,34.13) v2(3.28,33.24) v2(4.19,35.92) v2(4.19,35.03) v2(4.17,34.13) v2(4.17,33.24) v2(8.37,4.24) v2(8.37,3.48) v2(8.37,2.72) v2(8.37,1.96) v2(8.37,1.2) v2(8.37,0.43) v2(8.87,35.91) v2(8.87,35.02) v2(8.87,34.13) v2(8.87,33.24) v2(9.37,5.03) v2(9.37,4.26) v2(9.37,3.5) v2(9.37,2.74) v2(9.37,1.98) v2(9.37,1.22) v2(9.76,35.91) v2(9.76,35.02) v2(9.76,34.13) v2(9.76,33.24) v2(10.26,5.03) v2(10.26,4.26) v2(10.26,3.5) v2(10.26,2.74) v2(10.26,1.98) v2(10.26,1.22)
PGND: length 1.1
  BOTTOM w0.356: P1.5 18.39,31.7
  vias: v2(16.48,27.25) v2(16.48,26.24) v2(16.61,25.19) v2(17.25,26.36) v2(17.25,24.71) v2(17.37,27.25) v2(17.37,25.6) v2(17.38,23.95) v2(17.75,23.31) v2(17.88,29.41) v2(18.01,31.38) v2(18.01,24.79) v2(18.16,28.45) v2(18.63,24.2) v2(18.7,22.6) v2(18.92,28.45) v2(19.04,25.22) v2(19.15,31.44) v2(19.79,25.2) v2(21.18,23.69)
DISABLE: length 21.8
  TOP w0.305: R7.2 19.2,11.71 15.21,15.69 v1(15.21,19.76) ; A1.2 6.21,21.78 6.71,21.28 v1(7.09,21.28)
  BOTTOM w0.305: v1(7.09,21.28) 8.23,21.28 8.6,20.92 U3.4 8.6,20.41 9.25,19.76 v1(15.21,19.76)
UNNAMED_7_741G126_I166_A: length 10.4
  BOTTOM w0.305: U3.2 9.25,18.23 8.99,17.98 8.1,17.98 5.7,20.38 R5.1 4.18,20.38 3.78,20.77 1.98,20.77 1.45,20.24 U2.6
UNNAMED_7_741G126_I166_OE: length 1.9
  BOTTOM w0.305: R6.1 9.9,17.29 U3.1
UNNAMED_7_ADL5606_I18_RFIN: length 4.6
  TOP w0.305: 5.56,17.88 C1.2
  TOP w0.356: A1.1 5.56,21.35
  TOP w0.635: 5.56,21.35 CIN.2 5.56,17.88
UNNAMED_7_ADL5606_I18_RFOUT1: length 6.1
  TOP w0.457: C8.1 6.54,30.14 6.54,30.14
  TOP w0.635: 6.54,30.14 COUT.2 6.54,29.15 L2.1 6.54,26.53 A1.11 ; A1.9 A1.10 A1.11 ; A1.11 A1.12
UNNAMED_7_CAP_I76_N2: length 3.7
  TOP w0.457: 6.54,31.18 C8.2
  TOP w0.635: 6.54,31.18 6.54,34.83 J2.1
UNNAMED_7_CAP_I108_N2: length 0.8
  TOP w0.305: R2.2 v2(13.31,6.45)
UNNAMED_7_CAP_I113_N2:
  vias: v2(18.14,18.11) v2(18.14,17.47) v2(18.14,16.84) v2(18.77,16.84) v2(19.43,18.16) v2(20.57,18.16) v2(21.14,16.87) v2(21.84,18.16) v2(22.73,19.81) v2(22.73,19.05) v2(22.92,18.22) v2(23.75,17.53) v2(23.81,16.74) v2(23.94,18.41)
UNNAMED_7_CAP_I132_N2: length 3.7
  BOTTOM w0.305: C9.2 C6.2 11.07,15.34 U1.F1
UNNAMED_7_CN5P3SHLD_I127_N6: length 15.1
  BOTTOM w0.305: P1.SH1 15.72,35.29 15.72,34.74 16.1,34.74 16.43,34.42 18.1,34.42 19.19,35.51 P1.SH2 20.18,35.51 21.27,34.42 22.77,34.42 P1.SH3
  BOTTOM w0.762: R1.2 16.36,30.57 16.36,34.11 15.72,34.74
UNNAMED_7_DIOLED_I150_P: length 1.6
  TOP w0.305: R4.1 DS1.A
UNNAMED_7_DIOLED_I172_P: length 1.5
  TOP w0.305: R7.1 DS2.A
UNNAMED_7_FERRITE_I107_N1: length 12.5
  TOP w0.305: R4.2 21.08,10.11 20.8,10.11 20.23,9.53 20.23,4.84 v2(20.23,4.84) ; v2(15.34,2.87) 14.12,4.09 R3.2
  BOTTOM w0.305: C17.2 v2(20.23,4.84)
UNNAMED_7_LINLTM8045_I104_FB: length 4.2
  TOP w0.305: v2(15.09,7.95) 15.09,7.95 R2.1 R3.1
  BOTTOM w0.305: U1.A3 14.73,8.3 v2(15.09,7.95)
UNNAMED_7_LINLTM8045_I104_RT: length 2.7
  BOTTOM w0.305: U1.G1 11.66,16.08 10.31,16.08 RT.1

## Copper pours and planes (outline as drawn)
5V_VCC on TOP: 0.63,25.94 0.64,29.08 4.72,29.08 5.45,28.35 5.45,27.04 4.82,27.04 3.72,25.95
5V_VCC on TOP: 6.68,22.68 12.04,22.68 12.29,22.43 12.29,20.14 10.52,20.14 10.13,20.52 7.47,20.52 7.47,21.15 6.68,21.94
5V_VCC on BOTTOM: 2.72,18.23 3.94,18.23 3.94,16.2 3.78,16.05 2.87,16.05 2.72,16.2
5V_VCC on BOTTOM: 9.88,20.39 12.29,20.39 12.29,22.43 11.91,22.81 8.74,22.81 8.48,22.55 8.48,21.66 9.12,21.03 9.25,21.03
5V_VCC on BOTTOM: 4.1,22.93 5.92,22.93 6.07,22.78 6.07,21.71 4.88,21.71 4.13,20.97 2.51,20.97 2.12,21.36 2.12,21.6 1.9,21.82 1.19,21.82 1.19,22.93 2.69,22.93 2.69,21.73 2.9,21.52 3.71,21.52 4,21.82 4,22.83
5V_VCC on BOTTOM: 8.61,17.47 7.59,17.47 7.34,17.22 7.34,16.33 7.59,16.08 8.36,16.08 8.61,16.33
5V_VCC on BOTTOM: 11.4,5.41 13.06,5.41 13.31,5.15 13.31,2.49 11.4,2.49 11.15,2.74 11.15,5.15
5V_VCC on L4_PWR: 0.63,0.63 0.63,29.03 5.18,29.03 8.99,25.22 8.99,22.81 11.91,22.81 11.91,7.62 12.93,6.6 12.93,0.63
GND on TOP (solid shape): 6.79,13.03 4.38,13.03 4.38,13.79 6.79,13.79
GND on TOP: 7.37,36.96 12.12,36.96 12.12,36.36 15.21,36.36 15.21,24.33 17.88,21.66 21.52,21.66 21.52,19.12 17.63,19.12 17.12,18.62 17.12,16.33 18.26,15.19 24.77,15.19 24.77,0.63 11.09,0.63 11.09,0 0.48,0 0.48,5.66 0.63,5.66 0.63,25.42 5.36,25.42 5.36,25.45 8.2,25.45 8.2,26.87 7.37,27.7 ; 2 cut-outs
GND on TOP: 0.63,29.41 0.63,36.96 5.7,36.96 5.7,29.41
GND on BOTTOM: 0.63,36.96 12.12,36.96 12.12,36.36 15.21,36.36 15.21,24.33 17.88,21.66 21.51,21.66 21.51,19.12 15.85,19.12 14.1,17.37 14.1,16.18 15.09,15.19 24.78,15.19 24.77,6.93 24.77,0.63 11.09,0.63 11.09,0.07 0.48,0.07 0.48,5.66 0.63,5.66 ; 4 cut-outs
GND on L2_GND: 7.39,36.96 12.12,36.96 12.12,36.33 15.21,36.33 15.21,24.33 17.88,21.66 24.77,21.66 24.77,0.63 11.09,0.63 11.09,0 6.4,0 6.4,21.36 6.02,21.74 6.02,23.11 4.72,23.11 4.72,0 0.63,0 0.63,36.96 5.69,36.96 5.69,27.23 5.49,27.02 4.83,27.02 4.83,25.47 8.2,25.47 8.2,26.87 7.39,27.68
GND on L3_GND, L5_GND: 0.63,0 0.63,36.96 12.12,36.96 12.12,36.33 15.21,36.33 15.21,24.33 17.88,21.66 24.77,21.66 24.77,0.63 11.09,0.63 11.09,0
GND on L4_PWR: 12.42,0.63 12.42,23.31 9.5,23.31 9.5,25.6 5.69,29.41 0.63,29.41 0.63,36.36 15.21,36.36 15.21,24.33 17.88,21.66 24.78,21.66 24.77,0.63
PGND on TOP: 15.98,36.34 24.77,36.34 24.76,22.17 22.15,22.17 22.15,22.17 18.31,22.17 15.98,24.51
PGND on BOTTOM: 16.61,34.26 16.8,34.26 16.8,32.9 18.96,32.9 18.96,33.6 20.29,33.6 20.29,25.27 21.51,24.05 21.51,22.17 18.31,22.17 15.98,24.51 15.98,29.54 16.61,30.17
PGND on L2_GND, L3_GND, L5_GND: 15.98,36.34 24.76,36.34 24.77,22.17 18.32,22.17 15.98,24.51
PGND on L4_PWR: 15.98,36.34 24.76,36.34 24.76,22.17 22.15,22.17 22.15,22.17 21.91,22.17 18.32,22.17 15.98,24.51
UNNAMED_7_CAP_I108_N2 on BOTTOM: 11.53,10.49 13.52,10.49 14.22,9.78 14.22,8.43 15.21,7.44 15.21,6.04 11.66,6.04 11.4,6.3 11.4,7.31 10.9,7.82 8.48,7.82 8.48,9.22 10.26,9.22
UNNAMED_7_CAP_I113_N2 on TOP: 18.39,15.82 24.77,15.82 24.77,21.66 22.15,21.66 22.15,18.49 17.88,18.49 17.63,18.23 17.63,16.58
UNNAMED_7_CAP_I113_N2 on BOTTOM: 14.58,16.33 15.09,15.82 19.46,15.82 19.46,15.82 24.77,15.82 24.77,21.64 22.15,21.64 22.15,18.49 15.98,18.49 14.58,17.09
UNNAMED_7_CAP_I120_N2 on BOTTOM: 20.8,33.79 24.76,33.79 24.76,22.17 22.2,22.17 22.2,24.33 20.93,25.6 20.93,32.02 20.8,32.02
UNNAMED_7_FERRITE_I107_N1 on BOTTOM: 14.07,2.49 14.07,5.15 16.87,5.15 16.87,2.87 16.48,2.49

Small or netless copper shapes (teardrops, artwork): 2 on TOP

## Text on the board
Ref Des/Assembly Bottom: A | C
Ref Des/Silkscreen Bottom: WARNING: HOT SURFACE | A | C | SECONDARY SIDE | 08-046520 REV C Z
User.Comments: SEE DETAIL A | VIEWED FROM THE | PRIMARY SIDE | SCALE: NONE | DETAIL A | 4.    PARTS INDICATED BELOW SHOULD BE MOUNTED MANUALLY: | B.    J2, E028678, CONN-PCB EDGE SMA SMALL VERSION, CON-SMA-EDGE-S | A.    J1, E033180, CONN-PCB RCPT PLUG SMA END LAUNCH, 132365-10
Ref Des/Assembly Top: C | A
Ref Des/Silkscreen Top: UP TO 18DBM | WARNING: HOT SURFACE | EVAL-CN0417-EBZ | 08-046520 REV C Z | PRIMARY SIDE | A | C
DIMENSION: BOARD DIMENSIONS | ARRAY DRAWING | NON-PLATED: +/- 2 MILS | DIA MAX | SEE NOTE 14
PAGE_OUTLINE: B | C | C1 | C2 | C3 | AS PER ECR-077197, ECR-077830, AND ECR-079975 | AS PER ECR-087290 | AS PER ECR-089418 | AS PER ECR-089464 | AS PER ECR-089574 | 25JUL18 | 25JUN19 | 22JUL19 | 24JUL19 | 05AUG19 | T.CABILDO | CUSTOMER EVAL BOARD Z | PRIMARY SIDE
User.15: L5_GND PLANE    (LAYER 5) | L4_PWR PLANE    (LAYER 4) | 15.    BOARDS TO BE SHIPPED IN ARRAY | 3.5 MILS | 8.5 MILS | 50 OHMS
User.17: 08-      -07 | L2 GND
User.18: L3 GND | 08-      -08
User.19: L4 PWR | 08-      -09
User.20: L5 GND | 08-      -10
User.45: FIGURE | SIZE | 8.0 | 8.01 | 10.0 | 10.01 | 25.0 | 125.0 | 34.0x26.0 | 51.0x24.0 | DRILL CHART: TOP to BOTTOM | ALL UNITS ARE IN MILS | PLATED | NON-PLATED | QTY | 298 | 168 | 51 | 68 | 96 | 4 | 2 | TOLERANCE/NOTES
